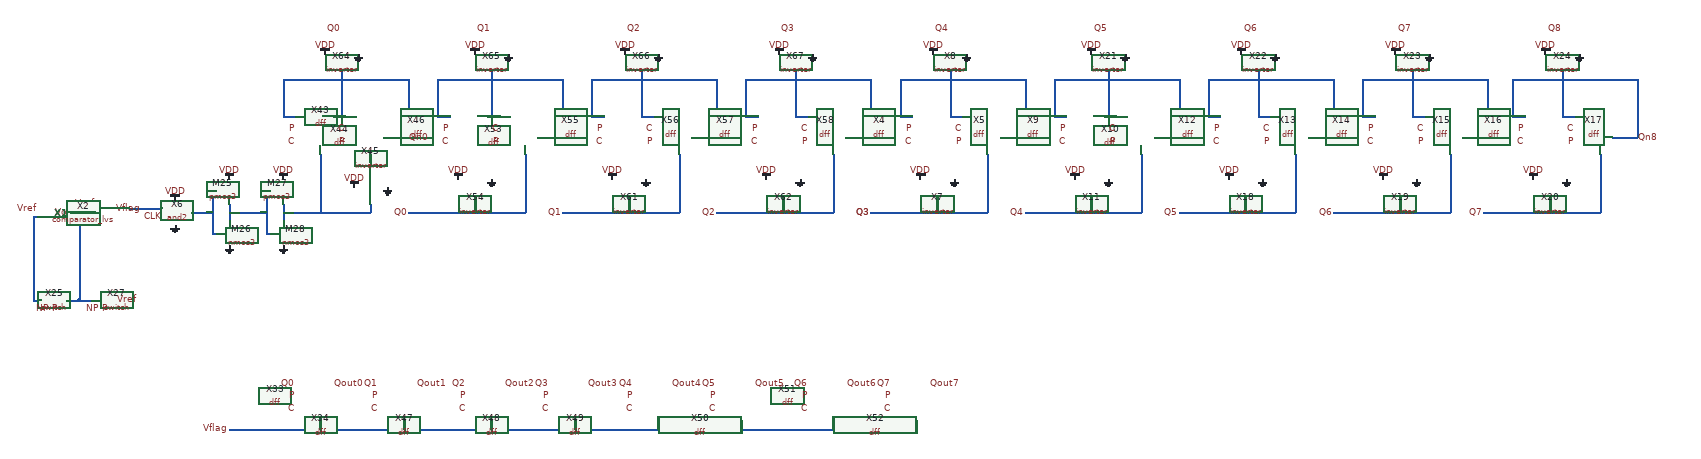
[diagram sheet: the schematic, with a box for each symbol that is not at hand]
v {xschem version=2.9.9 file_version=1.2 }
G {}
K {}
V {}
S {}
E {}
N 750 -640 770 -640 { lab=Vout}
N 710 -640 750 -640 { lab=Vout}
N 730 -640 730 -550 { lab=Vout}
N 620 -630 620 -550 { lab=#net1}
N 850 -650 930 -650 { lab=Vflag}
N 1090 -120 2740 -120 { lab=Vflag}
N 2740 -140 2740 -120 { lab=Vflag}
N 2540 -140 2540 -120 { lab=Vflag}
N 2320 -140 2320 -120 { lab=Vflag}
N 2120 -140 2120 -120 { lab=Vflag}
N 1920 -140 1920 -120 { lab=Vflag}
N 1720 -140 1720 -120 { lab=Vflag}
N 1510 -140 1510 -120 { lab=Vflag}
N 1310 -140 1310 -120 { lab=Vflag}
N 1310 -780 1310 -760 { lab=#net2}
N 1340 -870 1370 -870 { lab=#net3}
N 1460 -820 1520 -820 { lab=Qn0}
N 1520 -960 1520 -820 { lab=Qn0}
N 1220 -960 1520 -960 { lab=Qn0}
N 1220 -960 1220 -870 { lab=Qn0}
N 1220 -870 1250 -870 { lab=Qn0}
N 1430 -780 1430 -760 { lab=#net4}
N 1430 -660 1430 -640 { lab=#net2}
N 1310 -640 1430 -640 { lab=#net2}
N 1710 -870 1740 -870 { lab=#net5}
N 1830 -820 1890 -820 { lab=Qn1}
N 1890 -960 1890 -820 { lab=Qn1}
N 1590 -960 1890 -960 { lab=Qn1}
N 1590 -960 1590 -870 { lab=Qn1}
N 1590 -870 1620 -870 { lab=Qn1}
N 2080 -870 2110 -870 { lab=#net6}
N 2200 -820 2260 -820 { lab=Qn2}
N 2260 -960 2260 -820 { lab=Qn2}
N 1960 -960 2260 -960 { lab=Qn2}
N 1960 -960 1960 -870 { lab=Qn2}
N 1960 -870 1990 -870 { lab=Qn2}
N 2450 -870 2480 -870 { lab=#net7}
N 2570 -820 2630 -820 { lab=Qn3}
N 2630 -960 2630 -820 { lab=Qn3}
N 2330 -960 2630 -960 { lab=Qn3}
N 2330 -960 2330 -870 { lab=Qn3}
N 2330 -870 2360 -870 { lab=Qn3}
N 1800 -780 1800 -640 { lab=Q0}
N 1520 -640 1800 -640 { lab=Q0}
N 1680 -680 1680 -640 { lab=Q0}
N 2170 -780 2170 -640 { lab=Q1}
N 1890 -640 2170 -640 { lab=Q1}
N 2050 -680 2050 -640 { lab=Q1}
N 2540 -780 2540 -640 { lab=Q2}
N 2260 -640 2540 -640 { lab=Q2}
N 2420 -680 2420 -640 { lab=Q2}
N 1360 -980 1360 -870 { lab=#net3}
N 1720 -980 1720 -870 { lab=#net5}
N 2080 -980 2080 -870 { lab=#net6}
N 2450 -980 2450 -870 { lab=#net7}
N 1310 -660 1310 -640 { lab=#net2}
N 1310 -760 1310 -660 { lab=#net2}
N 2820 -870 2850 -870 { lab=#net8}
N 2940 -820 3000 -820 { lab=Qn4}
N 3000 -960 3000 -820 { lab=Qn4}
N 2700 -960 3000 -960 { lab=Qn4}
N 2700 -960 2700 -870 { lab=Qn4}
N 2700 -870 2730 -870 { lab=Qn4}
N 2910 -780 2910 -640 { lab=Q3}
N 2630 -640 2910 -640 { lab=Q3}
N 2790 -680 2790 -640 { lab=Q3}
N 2820 -980 2820 -870 { lab=#net8}
N 3190 -870 3220 -870 { lab=#net9}
N 3310 -820 3370 -820 { lab=Qn5}
N 3370 -960 3370 -820 { lab=Qn5}
N 3070 -960 3370 -960 { lab=Qn5}
N 3070 -960 3070 -870 { lab=Qn5}
N 3070 -870 3100 -870 { lab=Qn5}
N 3560 -870 3590 -870 { lab=#net10}
N 3680 -820 3740 -820 { lab=Qn6}
N 3740 -960 3740 -820 { lab=Qn6}
N 3440 -960 3740 -960 { lab=Qn6}
N 3440 -960 3440 -870 { lab=Qn6}
N 3440 -870 3470 -870 { lab=Qn6}
N 3930 -870 3960 -870 { lab=#net11}
N 4050 -820 4110 -820 { lab=Qn7}
N 4110 -960 4110 -820 { lab=Qn7}
N 3810 -960 4110 -960 { lab=Qn7}
N 3810 -960 3810 -870 { lab=Qn7}
N 3810 -870 3840 -870 { lab=Qn7}
N 3280 -780 3280 -640 { lab=Q4}
N 3000 -640 3280 -640 { lab=Q4}
N 3160 -680 3160 -640 { lab=Q4}
N 3650 -780 3650 -640 { lab=Q5}
N 3370 -640 3650 -640 { lab=Q5}
N 3530 -680 3530 -640 { lab=Q5}
N 4020 -780 4020 -640 { lab=Q6}
N 3740 -640 4020 -640 { lab=Q6}
N 3900 -680 3900 -640 { lab=Q6}
N 3200 -980 3200 -870 { lab=#net9}
N 3560 -980 3560 -870 { lab=#net10}
N 3930 -980 3930 -870 { lab=#net11}
N 4290 -870 4320 -870 { lab=#net12}
N 4410 -820 4470 -820 { lab=Qn8}
N 4470 -960 4470 -820 { lab=Qn8}
N 4170 -960 4470 -960 { lab=Qn8}
N 4170 -960 4170 -870 { lab=Qn8}
N 4170 -870 4200 -870 { lab=Qn8}
N 4380 -780 4380 -640 { lab=Q7}
N 4100 -640 4380 -640 { lab=Q7}
N 4260 -680 4260 -640 { lab=Q7}
N 4290 -980 4290 -870 { lab=#net12}
N 700 -430 730 -430 { lab=Vout}
N 730 -550 730 -430 { lab=Vout}
N 620 -550 620 -430 { lab=#net1}
N 620 -430 640 -430 { lab=#net1}
N 730 -430 760 -430 { lab=Vout}
N 620 -630 630 -630 { lab=#net1}
N 1090 -660 1090 -620 { lab=#net13}
N 1220 -660 1220 -620 { lab=#net2}
N 1050 -690 1060 -690 { lab=#net14}
N 1050 -690 1050 -590 { lab=#net14}
N 1050 -590 1060 -590 { lab=#net14}
N 1180 -690 1190 -690 { lab=#net13}
N 1180 -690 1180 -590 { lab=#net13}
N 1180 -590 1190 -590 { lab=#net13}
N 1090 -640 1180 -640 { lab=#net13}
N 1220 -640 1310 -640 { lab=#net2}
N 1000 -640 1050 -640 { lab=#net14}
C {devices/lab_pin.sym} 730 -640 1 0 {name=l2 sig_type=std_logic lab=Vout}
C {devices/lab_pin.sym} 630 -650 0 0 {name=l5 sig_type=std_logic lab=Vref}
C {devices/lab_pin.sym} 770 -660 1 0 {name=l9 sig_type=std_logic lab=Vref}
C {devices/lab_pin.sym} 880 -650 1 0 {name=l12 sig_type=std_logic lab=Vflag}
C {devices/lab_pin.sym} 930 -630 0 0 {name=l10 sig_type=std_logic lab=CLK}
C {/home/madvlsi/Documents/MADVLSI-Final_Project/schematic/and2.sym} 900 -640 0 0 {name=X6}
C {madvlsi/vdd.sym} 960 -670 0 0 {name=l62 lab=VDD}
C {madvlsi/gnd.sym} 960 -610 0 0 {name=l63 lab=GND}
C {/home/madvlsi/Documents/MADVLSI-Final_Project/schematic/dff.sym} 1200 -200 0 0 {name=X33}
C {/home/madvlsi/Documents/MADVLSI-Final_Project/schematic/dff.sym} 1400 -200 0 0 {name=X34}
C {devices/lab_pin.sym} 1090 -120 0 0 {name=l64 sig_type=std_logic lab=Vflag}
C {devices/lab_pin.sym} 1250 -230 0 0 {name=l69 sig_type=std_logic lab=Q0}
C {devices/lab_pin.sym} 1450 -230 0 0 {name=l70 sig_type=std_logic lab=Q1}
C {/home/madvlsi/Documents/MADVLSI-Final_Project/schematic/dff.sym} 1610 -200 0 0 {name=X47}
C {/home/madvlsi/Documents/MADVLSI-Final_Project/schematic/dff.sym} 1810 -200 0 0 {name=X48}
C {devices/lab_pin.sym} 1660 -230 0 0 {name=l92 sig_type=std_logic lab=Q2}
C {devices/lab_pin.sym} 1860 -230 0 0 {name=l93 sig_type=std_logic lab=Q3}
C {/home/madvlsi/Documents/MADVLSI-Final_Project/schematic/dff.sym} 2010 -200 0 0 {name=X49}
C {/home/madvlsi/Documents/MADVLSI-Final_Project/schematic/dff.sym} 2210 -200 0 0 {name=X50}
C {devices/lab_pin.sym} 2060 -230 0 0 {name=l94 sig_type=std_logic lab=Q4}
C {devices/lab_pin.sym} 2260 -230 0 0 {name=l95 sig_type=std_logic lab=Q5}
C {/home/madvlsi/Documents/MADVLSI-Final_Project/schematic/dff.sym} 2430 -200 0 0 {name=X51}
C {/home/madvlsi/Documents/MADVLSI-Final_Project/schematic/dff.sym} 2630 -200 0 0 {name=X52}
C {devices/lab_pin.sym} 2480 -230 0 0 {name=l96 sig_type=std_logic lab=Q6}
C {devices/lab_pin.sym} 2680 -230 0 0 {name=l97 sig_type=std_logic lab=Q7}
C {devices/lab_pin.sym} 1340 -230 2 0 {name=l98 sig_type=std_logic lab=Qout0}
C {devices/lab_pin.sym} 1540 -230 2 0 {name=l99 sig_type=std_logic lab=Qout1}
C {devices/lab_pin.sym} 1750 -230 2 0 {name=l100 sig_type=std_logic lab=Qout2}
C {devices/lab_pin.sym} 1950 -230 2 0 {name=l101 sig_type=std_logic lab=Qout3}
C {devices/lab_pin.sym} 2150 -230 2 0 {name=l102 sig_type=std_logic lab=Qout4}
C {devices/lab_pin.sym} 2350 -230 2 0 {name=l103 sig_type=std_logic lab=Qout5}
C {devices/lab_pin.sym} 2570 -230 2 0 {name=l104 sig_type=std_logic lab=Qout6}
C {devices/lab_pin.sym} 2770 -230 2 0 {name=l105 sig_type=std_logic lab=Qout7}
C {devices/lab_pin.sym} 1360 -1080 1 0 {name=l85 sig_type=std_logic lab=Q0}
C {/home/madvlsi/Documents/MADVLSI-Final_Project/schematic/dff.sym} 1200 -840 0 0 {name=X43}
C {/home/madvlsi/Documents/MADVLSI-Final_Project/schematic/dff.sym} 1320 -840 0 0 {name=X44}
C {/home/madvlsi/Documents/MADVLSI-Final_Project/schematic/inverter.sym} 1430 -700 3 0 {name=X45 Wp=1 Lp=0.15 WW=1 LL=0.15}
C {madvlsi/vdd.sym} 1390 -700 3 0 {name=l87 lab=VDD}
C {madvlsi/gnd.sym} 1470 -700 3 0 {name=l88 lab=GND}
C {devices/lab_pin.sym} 1720 -1080 1 0 {name=l89 sig_type=std_logic lab=Q1}
C {/home/madvlsi/Documents/MADVLSI-Final_Project/schematic/dff.sym} 1570 -840 0 0 {name=X46}
C {/home/madvlsi/Documents/MADVLSI-Final_Project/schematic/dff.sym} 1690 -840 0 0 {name=X53}
C {/home/madvlsi/Documents/MADVLSI-Final_Project/schematic/inverter.sym} 1680 -720 3 0 {name=X54 Wp=1 Lp=0.15 WW=1 LL=0.15}
C {madvlsi/vdd.sym} 1640 -720 3 0 {name=l90 lab=VDD}
C {madvlsi/gnd.sym} 1720 -720 3 0 {name=l91 lab=GND}
C {devices/lab_pin.sym} 1520 -820 2 0 {name=l106 sig_type=std_logic lab=Qn0}
C {devices/lab_pin.sym} 1890 -820 2 0 {name=l107 sig_type=std_logic lab=Qn1}
C {devices/lab_pin.sym} 2080 -1080 1 0 {name=l108 sig_type=std_logic lab=Q2}
C {/home/madvlsi/Documents/MADVLSI-Final_Project/schematic/dff.sym} 1940 -840 0 0 {name=X55}
C {/home/madvlsi/Documents/MADVLSI-Final_Project/schematic/dff.sym} 2060 -840 0 0 {name=X56}
C {devices/lab_pin.sym} 2260 -820 2 0 {name=l109 sig_type=std_logic lab=Qn2}
C {devices/lab_pin.sym} 2450 -1080 1 0 {name=l110 sig_type=std_logic lab=Q3}
C {/home/madvlsi/Documents/MADVLSI-Final_Project/schematic/dff.sym} 2310 -840 0 0 {name=X57}
C {/home/madvlsi/Documents/MADVLSI-Final_Project/schematic/dff.sym} 2430 -840 0 0 {name=X58}
C {devices/lab_pin.sym} 2630 -820 2 0 {name=l111 sig_type=std_logic lab=Qn3}
C {/home/madvlsi/Documents/MADVLSI-Final_Project/schematic/inverter.sym} 2050 -720 3 0 {name=X61 Wp=1 Lp=0.15 WW=1 LL=0.15}
C {madvlsi/vdd.sym} 2010 -720 3 0 {name=l114 lab=VDD}
C {madvlsi/gnd.sym} 2090 -720 3 0 {name=l115 lab=GND}
C {/home/madvlsi/Documents/MADVLSI-Final_Project/schematic/inverter.sym} 2420 -720 3 0 {name=X62 Wp=1 Lp=0.15 WW=1 LL=0.15}
C {madvlsi/vdd.sym} 2380 -720 3 0 {name=l116 lab=VDD}
C {madvlsi/gnd.sym} 2460 -720 3 0 {name=l117 lab=GND}
C {/home/madvlsi/Documents/MADVLSI-Final_Project/schematic/inverter.sym} 1360 -1020 3 0 {name=X64 Wp=1 Lp=0.15 WW=1 LL=0.15}
C {madvlsi/vdd.sym} 1320 -1020 3 0 {name=l120 lab=VDD}
C {madvlsi/gnd.sym} 1400 -1020 3 0 {name=l121 lab=GND}
C {/home/madvlsi/Documents/MADVLSI-Final_Project/schematic/inverter.sym} 1720 -1020 3 0 {name=X65 Wp=1 Lp=0.15 WW=1 LL=0.15}
C {madvlsi/vdd.sym} 1680 -1020 3 0 {name=l122 lab=VDD}
C {madvlsi/gnd.sym} 1760 -1020 3 0 {name=l123 lab=GND}
C {/home/madvlsi/Documents/MADVLSI-Final_Project/schematic/inverter.sym} 2080 -1020 3 0 {name=X66 Wp=1 Lp=0.15 WW=1 LL=0.15}
C {madvlsi/vdd.sym} 2040 -1020 3 0 {name=l124 lab=VDD}
C {madvlsi/gnd.sym} 2120 -1020 3 0 {name=l125 lab=GND}
C {/home/madvlsi/Documents/MADVLSI-Final_Project/schematic/inverter.sym} 2450 -1020 3 0 {name=X67 Wp=1 Lp=0.15 WW=1 LL=0.15}
C {madvlsi/vdd.sym} 2410 -1020 3 0 {name=l126 lab=VDD}
C {madvlsi/gnd.sym} 2490 -1020 3 0 {name=l127 lab=GND}
C {devices/lab_pin.sym} 1520 -640 0 0 {name=l129 sig_type=std_logic lab=Q0}
C {devices/lab_pin.sym} 1890 -640 0 0 {name=l130 sig_type=std_logic lab=Q1}
C {devices/lab_pin.sym} 2260 -640 0 0 {name=l131 sig_type=std_logic lab=Q2}
C {devices/lab_pin.sym} 2630 -640 0 0 {name=l132 sig_type=std_logic lab=Q3}
C {devices/lab_pin.sym} 1250 -840 0 0 {name=l139 sig_type=std_logic lab=P}
C {devices/lab_pin.sym} 1250 -810 0 0 {name=l140 sig_type=std_logic lab=C}
C {devices/lab_pin.sym} 1370 -810 0 0 {name=l141 sig_type=std_logic lab=P}
C {devices/lab_pin.sym} 1370 -840 0 0 {name=l142 sig_type=std_logic lab=C}
C {devices/lab_pin.sym} 1620 -840 0 0 {name=l143 sig_type=std_logic lab=P}
C {devices/lab_pin.sym} 1620 -810 0 0 {name=l144 sig_type=std_logic lab=C}
C {devices/lab_pin.sym} 1990 -840 0 0 {name=l145 sig_type=std_logic lab=P}
C {devices/lab_pin.sym} 1990 -810 0 0 {name=l146 sig_type=std_logic lab=C}
C {devices/lab_pin.sym} 2360 -840 0 0 {name=l147 sig_type=std_logic lab=P}
C {devices/lab_pin.sym} 2360 -810 0 0 {name=l148 sig_type=std_logic lab=C}
C {devices/lab_pin.sym} 1740 -810 0 0 {name=l151 sig_type=std_logic lab=P}
C {devices/lab_pin.sym} 1740 -840 0 0 {name=l152 sig_type=std_logic lab=C}
C {devices/lab_pin.sym} 2110 -810 0 0 {name=l153 sig_type=std_logic lab=P}
C {devices/lab_pin.sym} 2110 -840 0 0 {name=l154 sig_type=std_logic lab=C}
C {devices/lab_pin.sym} 2480 -810 0 0 {name=l155 sig_type=std_logic lab=P}
C {devices/lab_pin.sym} 2480 -840 0 0 {name=l156 sig_type=std_logic lab=C}
C {devices/lab_pin.sym} 2820 -1080 1 0 {name=l11 sig_type=std_logic lab=Q4}
C {/home/madvlsi/Documents/MADVLSI-Final_Project/schematic/dff.sym} 2680 -840 0 0 {name=X4}
C {/home/madvlsi/Documents/MADVLSI-Final_Project/schematic/dff.sym} 2800 -840 0 0 {name=X5}
C {devices/lab_pin.sym} 3000 -820 2 0 {name=l15 sig_type=std_logic lab=Qn4}
C {/home/madvlsi/Documents/MADVLSI-Final_Project/schematic/inverter.sym} 2790 -720 3 0 {name=X7 Wp=1 Lp=0.15 WW=1 LL=0.15}
C {madvlsi/vdd.sym} 2750 -720 3 0 {name=l16 lab=VDD}
C {madvlsi/gnd.sym} 2830 -720 3 0 {name=l17 lab=GND}
C {devices/lab_pin.sym} 2630 -640 0 0 {name=l18 sig_type=std_logic lab=Q3}
C {/home/madvlsi/Documents/MADVLSI-Final_Project/schematic/inverter.sym} 2820 -1020 3 0 {name=X8 Wp=1 Lp=0.15 WW=1 LL=0.15}
C {madvlsi/vdd.sym} 2780 -1020 3 0 {name=l19 lab=VDD}
C {madvlsi/gnd.sym} 2860 -1020 3 0 {name=l20 lab=GND}
C {devices/lab_pin.sym} 2730 -840 0 0 {name=l21 sig_type=std_logic lab=P}
C {devices/lab_pin.sym} 2730 -810 0 0 {name=l24 sig_type=std_logic lab=C}
C {devices/lab_pin.sym} 2850 -810 0 0 {name=l27 sig_type=std_logic lab=P}
C {devices/lab_pin.sym} 2850 -840 0 0 {name=l28 sig_type=std_logic lab=C}
C {devices/lab_pin.sym} 3200 -1080 1 0 {name=l29 sig_type=std_logic lab=Q5}
C {/home/madvlsi/Documents/MADVLSI-Final_Project/schematic/dff.sym} 3050 -840 0 0 {name=X9}
C {/home/madvlsi/Documents/MADVLSI-Final_Project/schematic/dff.sym} 3170 -840 0 0 {name=X10}
C {/home/madvlsi/Documents/MADVLSI-Final_Project/schematic/inverter.sym} 3160 -720 3 0 {name=X11 Wp=1 Lp=0.15 WW=1 LL=0.15}
C {madvlsi/vdd.sym} 3120 -720 3 0 {name=l30 lab=VDD}
C {madvlsi/gnd.sym} 3200 -720 3 0 {name=l31 lab=GND}
C {devices/lab_pin.sym} 3370 -820 2 0 {name=l32 sig_type=std_logic lab=Qn5}
C {devices/lab_pin.sym} 3560 -1080 1 0 {name=l33 sig_type=std_logic lab=Q6}
C {/home/madvlsi/Documents/MADVLSI-Final_Project/schematic/dff.sym} 3420 -840 0 0 {name=X12}
C {/home/madvlsi/Documents/MADVLSI-Final_Project/schematic/dff.sym} 3540 -840 0 0 {name=X13}
C {devices/lab_pin.sym} 3740 -820 2 0 {name=l34 sig_type=std_logic lab=Qn6}
C {devices/lab_pin.sym} 3930 -1080 1 0 {name=l35 sig_type=std_logic lab=Q7}
C {/home/madvlsi/Documents/MADVLSI-Final_Project/schematic/dff.sym} 3790 -840 0 0 {name=X14}
C {/home/madvlsi/Documents/MADVLSI-Final_Project/schematic/dff.sym} 3910 -840 0 0 {name=X15}
C {devices/lab_pin.sym} 4110 -820 2 0 {name=l36 sig_type=std_logic lab=Qn7}
C {/home/madvlsi/Documents/MADVLSI-Final_Project/schematic/inverter.sym} 3530 -720 3 0 {name=X18 Wp=1 Lp=0.15 WW=1 LL=0.15}
C {madvlsi/vdd.sym} 3490 -720 3 0 {name=l39 lab=VDD}
C {madvlsi/gnd.sym} 3570 -720 3 0 {name=l40 lab=GND}
C {/home/madvlsi/Documents/MADVLSI-Final_Project/schematic/inverter.sym} 3900 -720 3 0 {name=X19 Wp=1 Lp=0.15 WW=1 LL=0.15}
C {madvlsi/vdd.sym} 3860 -720 3 0 {name=l41 lab=VDD}
C {madvlsi/gnd.sym} 3940 -720 3 0 {name=l42 lab=GND}
C {/home/madvlsi/Documents/MADVLSI-Final_Project/schematic/inverter.sym} 3200 -1020 3 0 {name=X21 Wp=1 Lp=0.15 WW=1 LL=0.15}
C {madvlsi/vdd.sym} 3160 -1020 3 0 {name=l45 lab=VDD}
C {madvlsi/gnd.sym} 3240 -1020 3 0 {name=l46 lab=GND}
C {/home/madvlsi/Documents/MADVLSI-Final_Project/schematic/inverter.sym} 3560 -1020 3 0 {name=X22 Wp=1 Lp=0.15 WW=1 LL=0.15}
C {madvlsi/vdd.sym} 3520 -1020 3 0 {name=l47 lab=VDD}
C {madvlsi/gnd.sym} 3600 -1020 3 0 {name=l48 lab=GND}
C {/home/madvlsi/Documents/MADVLSI-Final_Project/schematic/inverter.sym} 3930 -1020 3 0 {name=X23 Wp=1 Lp=0.15 WW=1 LL=0.15}
C {madvlsi/vdd.sym} 3890 -1020 3 0 {name=l49 lab=VDD}
C {madvlsi/gnd.sym} 3970 -1020 3 0 {name=l50 lab=GND}
C {devices/lab_pin.sym} 3000 -640 0 0 {name=l51 sig_type=std_logic lab=Q4}
C {devices/lab_pin.sym} 3370 -640 0 0 {name=l52 sig_type=std_logic lab=Q5}
C {devices/lab_pin.sym} 3740 -640 0 0 {name=l53 sig_type=std_logic lab=Q6}
C {devices/lab_pin.sym} 3100 -840 0 0 {name=l57 sig_type=std_logic lab=P}
C {devices/lab_pin.sym} 3100 -810 0 0 {name=l58 sig_type=std_logic lab=C}
C {devices/lab_pin.sym} 3470 -840 0 0 {name=l59 sig_type=std_logic lab=P}
C {devices/lab_pin.sym} 3470 -810 0 0 {name=l60 sig_type=std_logic lab=C}
C {devices/lab_pin.sym} 3840 -840 0 0 {name=l61 sig_type=std_logic lab=P}
C {devices/lab_pin.sym} 3840 -810 0 0 {name=l65 sig_type=std_logic lab=C}
C {devices/lab_pin.sym} 3220 -810 0 0 {name=l68 sig_type=std_logic lab=P}
C {devices/lab_pin.sym} 3220 -840 0 0 {name=l71 sig_type=std_logic lab=C}
C {devices/lab_pin.sym} 3590 -810 0 0 {name=l72 sig_type=std_logic lab=P}
C {devices/lab_pin.sym} 3590 -840 0 0 {name=l73 sig_type=std_logic lab=C}
C {devices/lab_pin.sym} 3960 -810 0 0 {name=l74 sig_type=std_logic lab=P}
C {devices/lab_pin.sym} 3960 -840 0 0 {name=l75 sig_type=std_logic lab=C}
C {devices/lab_pin.sym} 4290 -1080 1 0 {name=l37 sig_type=std_logic lab=Q8}
C {/home/madvlsi/Documents/MADVLSI-Final_Project/schematic/dff.sym} 4150 -840 0 0 {name=X16}
C {/home/madvlsi/Documents/MADVLSI-Final_Project/schematic/dff.sym} 4270 -840 0 0 {name=X17}
C {devices/lab_pin.sym} 4470 -820 2 0 {name=l38 sig_type=std_logic lab=Qn8}
C {/home/madvlsi/Documents/MADVLSI-Final_Project/schematic/inverter.sym} 4260 -720 3 0 {name=X20 Wp=1 Lp=0.15 WW=1 LL=0.15}
C {madvlsi/vdd.sym} 4220 -720 3 0 {name=l43 lab=VDD}
C {madvlsi/gnd.sym} 4300 -720 3 0 {name=l44 lab=GND}
C {/home/madvlsi/Documents/MADVLSI-Final_Project/schematic/inverter.sym} 4290 -1020 3 0 {name=X24 Wp=1 Lp=0.15 WW=1 LL=0.15}
C {madvlsi/vdd.sym} 4250 -1020 3 0 {name=l54 lab=VDD}
C {madvlsi/gnd.sym} 4330 -1020 3 0 {name=l55 lab=GND}
C {devices/lab_pin.sym} 4100 -640 0 0 {name=l56 sig_type=std_logic lab=Q7}
C {devices/lab_pin.sym} 4200 -840 0 0 {name=l66 sig_type=std_logic lab=P}
C {devices/lab_pin.sym} 4200 -810 0 0 {name=l67 sig_type=std_logic lab=C}
C {devices/lab_pin.sym} 4320 -810 0 0 {name=l76 sig_type=std_logic lab=P}
C {devices/lab_pin.sym} 4320 -840 0 0 {name=l77 sig_type=std_logic lab=C}
C {devices/lab_pin.sym} 1250 -200 0 0 {name=l78 sig_type=std_logic lab=P}
C {devices/lab_pin.sym} 1250 -170 0 0 {name=l79 sig_type=std_logic lab=C}
C {devices/lab_pin.sym} 1450 -200 0 0 {name=l80 sig_type=std_logic lab=P}
C {devices/lab_pin.sym} 1450 -170 0 0 {name=l81 sig_type=std_logic lab=C}
C {devices/lab_pin.sym} 1660 -200 0 0 {name=l82 sig_type=std_logic lab=P}
C {devices/lab_pin.sym} 1660 -170 0 0 {name=l83 sig_type=std_logic lab=C}
C {devices/lab_pin.sym} 1860 -200 0 0 {name=l84 sig_type=std_logic lab=P}
C {devices/lab_pin.sym} 1860 -170 0 0 {name=l86 sig_type=std_logic lab=C}
C {devices/lab_pin.sym} 2060 -200 0 0 {name=l128 sig_type=std_logic lab=P}
C {devices/lab_pin.sym} 2060 -170 0 0 {name=l159 sig_type=std_logic lab=C}
C {devices/lab_pin.sym} 2260 -200 0 0 {name=l160 sig_type=std_logic lab=P}
C {devices/lab_pin.sym} 2260 -170 0 0 {name=l161 sig_type=std_logic lab=C}
C {devices/lab_pin.sym} 2480 -200 0 0 {name=l162 sig_type=std_logic lab=P}
C {devices/lab_pin.sym} 2480 -170 0 0 {name=l163 sig_type=std_logic lab=C}
C {devices/lab_pin.sym} 2680 -200 0 0 {name=l164 sig_type=std_logic lab=P}
C {devices/lab_pin.sym} 2680 -170 0 0 {name=l165 sig_type=std_logic lab=C}
C {/home/madvlsi/Documents/MADVLSI-Final_Project/schematic/switch.sym} 670 -430 0 0 {name=X25 Wp=1 Lp=0.15 WW=1 LL=0.15}
C {devices/lab_pin.sym} 680 -410 3 0 {name=l112 sig_type=std_logic lab=P}
C {devices/lab_pin.sym} 660 -410 3 0 {name=l134 sig_type=std_logic lab=NP}
C {/home/madvlsi/Documents/MADVLSI-Final_Project/schematic/switch.sym} 790 -430 0 0 {name=X27 Wp=1 Lp=0.15 WW=1 LL=0.15}
C {devices/lab_pin.sym} 820 -430 2 0 {name=l149 sig_type=std_logic lab=Vref}
C {devices/lab_pin.sym} 800 -410 3 0 {name=l150 sig_type=std_logic lab=P}
C {devices/lab_pin.sym} 780 -410 3 0 {name=l157 sig_type=std_logic lab=NP}
C {/home/madvlsi/Documents/MADVLSI-Final_Project/schematic/selfbiasedcascode2stage_lvs.sym} 670 -640 0 0 {name=X1}
C {/home/madvlsi/Documents/MADVLSI-Final_Project/schematic/comparator_lvs.sym} 810 -650 0 0 {name=X2}
C {madvlsi/pmos3.sym} 1090 -690 0 0 {name=M25
L=0.15
W=2
body=VDD
nf=1
mult=1
ad="'int((nf+1)/2) * W/nf * 0.29'" 
pd="'2*int((nf+1)/2) * (W/nf + 0.29)'"
as="'int((nf+2)/2) * W/nf * 0.29'" 
ps="'2*int((nf+2)/2) * (W/nf + 0.29)'"
nrd="'0.29 / W'" nrs="'0.29 / W'"
sa=0 sb=0 sd=0
model=pfet_01v8
spiceprefix=X
}
C {madvlsi/vdd.sym} 1090 -720 0 0 {name=l14 lab=VDD}
C {madvlsi/nmos3.sym} 1090 -590 0 0 {name=M26
L=0.15
W=1
body=GND
nf=1
mult=1
ad="'int((nf+1)/2) * W/nf * 0.29'" 
pd="'2*int((nf+1)/2) * (W/nf + 0.29)'"
as="'int((nf+2)/2) * W/nf * 0.29'" 
ps="'2*int((nf+2)/2) * (W/nf + 0.29)'"
nrd="'0.29 / W'" nrs="'0.29 / W'"
sa=0 sb=0 sd=0
model=nfet_01v8
spiceprefix=X
}
C {madvlsi/gnd.sym} 1090 -560 0 0 {name=l1 lab=GND}
C {madvlsi/pmos3.sym} 1220 -690 0 0 {name=M27
L=0.15
W=12
body=VDD
nf=1
mult=1
ad="'int((nf+1)/2) * W/nf * 0.29'" 
pd="'2*int((nf+1)/2) * (W/nf + 0.29)'"
as="'int((nf+2)/2) * W/nf * 0.29'" 
ps="'2*int((nf+2)/2) * (W/nf + 0.29)'"
nrd="'0.29 / W'" nrs="'0.29 / W'"
sa=0 sb=0 sd=0
model=pfet_01v8
spiceprefix=X
}
C {madvlsi/vdd.sym} 1220 -720 0 0 {name=l3 lab=VDD}
C {madvlsi/nmos3.sym} 1220 -590 0 0 {name=M28
L=0.15
W=6
body=GND
nf=1
mult=1
ad="'int((nf+1)/2) * W/nf * 0.29'" 
pd="'2*int((nf+1)/2) * (W/nf + 0.29)'"
as="'int((nf+2)/2) * W/nf * 0.29'" 
ps="'2*int((nf+2)/2) * (W/nf + 0.29)'"
nrd="'0.29 / W'" nrs="'0.29 / W'"
sa=0 sb=0 sd=0
model=nfet_01v8
spiceprefix=X
}
C {madvlsi/gnd.sym} 1220 -560 0 0 {name=l4 lab=GND}
